VERSION 5.8 ;
BUSBITCHARS "[]" ;
DIVIDERCHAR "/" ;
UNITS
  DATABASE MICRONS 1000 ;
END UNITS
MANUFACTURINGGRID 0.01 ;
PROPERTYDEFINITIONS
  LAYER LEF58_RIGHTWAYONGRIDONLY STRING ;
END PROPERTYDEFINITIONS
LAYER masterslice
  TYPE MASTERSLICE ;
END masterslice
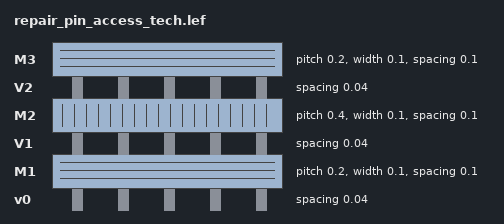
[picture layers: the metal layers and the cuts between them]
LAYER v0
  TYPE CUT ;
  SPACING 0.04 ;
END v0
LAYER M1
  TYPE ROUTING ;
  DIRECTION HORIZONTAL ;
  PITCH 0.2 ;
  WIDTH 0.1 ;
  SPACING 0.1 ;
END M1
LAYER V1
  TYPE CUT ;
  SPACING 0.04 ;
END V1
LAYER M2
  TYPE ROUTING ;
  DIRECTION VERTICAL ;
  PITCH 0.4 ;
  WIDTH 0.1 ;
  SPACING 0.1 ;
  PROPERTY LEF58_RIGHTWAYONGRIDONLY "RIGHTWAYONGRIDONLY ;" ;
END M2
VIA V12 DEFAULT
  LAYER M1 ;
    RECT -0.05 -0.05 0.05 0.05 ;
  LAYER V1 ;
    RECT -0.02 -0.02 0.02 0.02 ;
  LAYER M2 ;
    RECT -0.05 -0.05 0.05 0.05 ;
END V12
LAYER V2
  TYPE CUT ;
  SPACING 0.04 ;
END V2
LAYER M3
  TYPE ROUTING ;
  DIRECTION HORIZONTAL ;
  PITCH 0.2 ;
  WIDTH 0.1 ;
  SPACING 0.1 ;
END M3
VIA V23 DEFAULT
  LAYER M2 ;
    RECT -0.07 -0.07 0.07 0.07 ;
  LAYER V2 ;
    RECT -0.02 -0.02 0.02 0.02 ;
  LAYER M3 ;
    RECT -0.05 -0.05 0.05 0.05 ;
END V23
END LIBRARY
